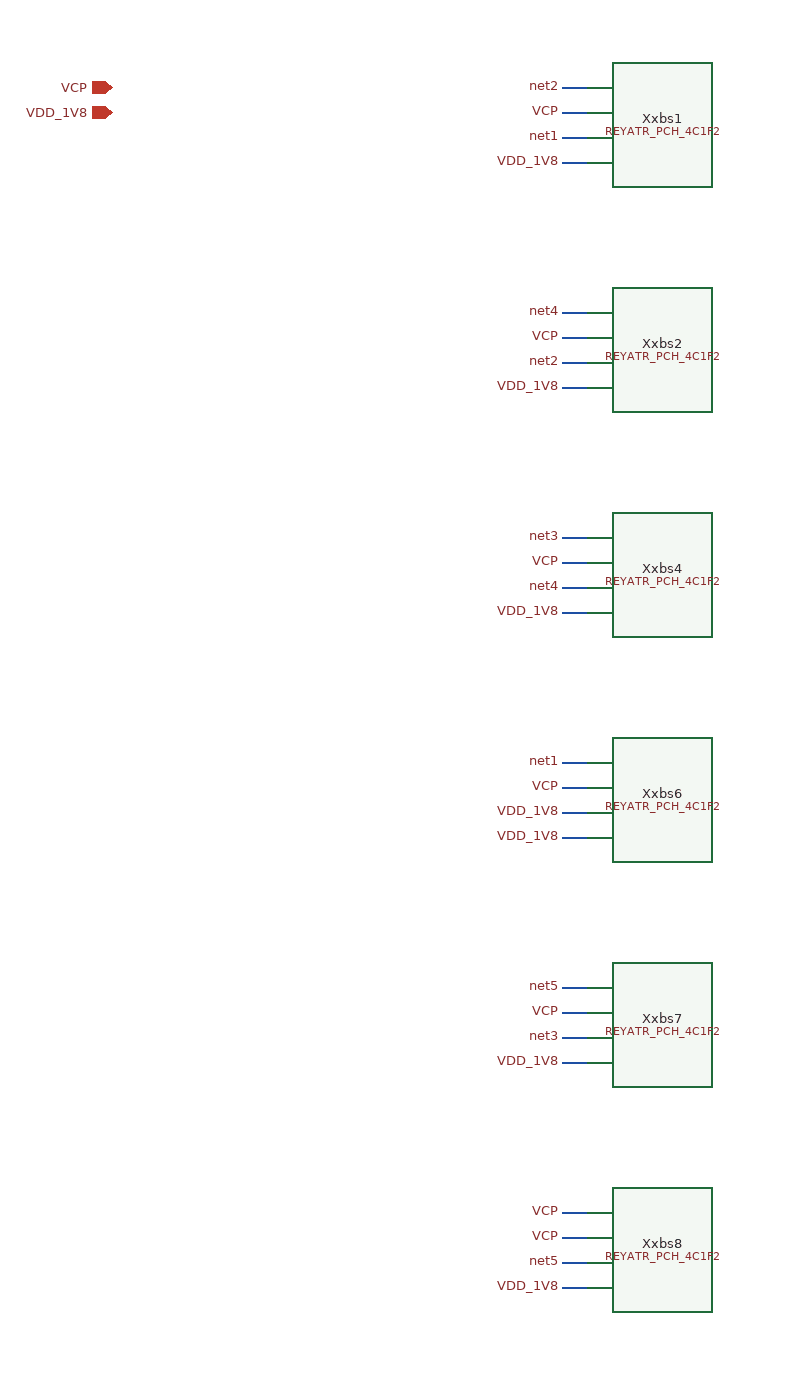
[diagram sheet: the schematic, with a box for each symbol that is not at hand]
v {xschem version=3.0.0 file_version=1.2 }
G {}
K {}
V {}
S {}
E {}
C {devices/iopin.sym} 0 0 0 0 {name=p0 lab=VCP}
C {devices/iopin.sym} 0 20 0 0 {name=p1 lab=VDD_1V8}
C {LELO_TEMP_SKY130A/REYATR_PCH_4C1F2.sym} 400 0 0 0 {name=Xxbs1}
N 360.0 0.0 380.0 0.0 {lab=net2}
C {devices/lab_pin.sym} 360.0 0.0 0 0 {name=l0 sig_type=std_logic lab=net2 }
N 360.0 20.0 380.0 20.0 {lab=VCP}
C {devices/lab_pin.sym} 360.0 20.0 0 0 {name=l1 sig_type=std_logic lab=VCP }
N 360.0 40.0 380.0 40.0 {lab=net1}
C {devices/lab_pin.sym} 360.0 40.0 0 0 {name=l2 sig_type=std_logic lab=net1 }
N 360.0 60.0 380.0 60.0 {lab=VDD_1V8}
C {devices/lab_pin.sym} 360.0 60.0 0 0 {name=l3 sig_type=std_logic lab=VDD_1V8 }
C {LELO_TEMP_SKY130A/REYATR_PCH_4C1F2.sym} 400 180.0 0 0 {name=Xxbs2}
N 360.0 180.0 380.0 180.0 {lab=net4}
C {devices/lab_pin.sym} 360.0 180.0 0 0 {name=l4 sig_type=std_logic lab=net4 }
N 360.0 200.0 380.0 200.0 {lab=VCP}
C {devices/lab_pin.sym} 360.0 200.0 0 0 {name=l5 sig_type=std_logic lab=VCP }
N 360.0 220.0 380.0 220.0 {lab=net2}
C {devices/lab_pin.sym} 360.0 220.0 0 0 {name=l6 sig_type=std_logic lab=net2 }
N 360.0 240.0 380.0 240.0 {lab=VDD_1V8}
C {devices/lab_pin.sym} 360.0 240.0 0 0 {name=l7 sig_type=std_logic lab=VDD_1V8 }
C {LELO_TEMP_SKY130A/REYATR_PCH_4C1F2.sym} 400 360.0 0 0 {name=Xxbs4}
N 360.0 360.0 380.0 360.0 {lab=net3}
C {devices/lab_pin.sym} 360.0 360.0 0 0 {name=l8 sig_type=std_logic lab=net3 }
N 360.0 380.0 380.0 380.0 {lab=VCP}
C {devices/lab_pin.sym} 360.0 380.0 0 0 {name=l9 sig_type=std_logic lab=VCP }
N 360.0 400.0 380.0 400.0 {lab=net4}
C {devices/lab_pin.sym} 360.0 400.0 0 0 {name=l10 sig_type=std_logic lab=net4 }
N 360.0 420.0 380.0 420.0 {lab=VDD_1V8}
C {devices/lab_pin.sym} 360.0 420.0 0 0 {name=l11 sig_type=std_logic lab=VDD_1V8 }
C {LELO_TEMP_SKY130A/REYATR_PCH_4C1F2.sym} 400 540.0 0 0 {name=Xxbs6}
N 360.0 540.0 380.0 540.0 {lab=net1}
C {devices/lab_pin.sym} 360.0 540.0 0 0 {name=l12 sig_type=std_logic lab=net1 }
N 360.0 560.0 380.0 560.0 {lab=VCP}
C {devices/lab_pin.sym} 360.0 560.0 0 0 {name=l13 sig_type=std_logic lab=VCP }
N 360.0 580.0 380.0 580.0 {lab=VDD_1V8}
C {devices/lab_pin.sym} 360.0 580.0 0 0 {name=l14 sig_type=std_logic lab=VDD_1V8 }
N 360.0 600.0 380.0 600.0 {lab=VDD_1V8}
C {devices/lab_pin.sym} 360.0 600.0 0 0 {name=l15 sig_type=std_logic lab=VDD_1V8 }
C {LELO_TEMP_SKY130A/REYATR_PCH_4C1F2.sym} 400 720.0 0 0 {name=Xxbs7}
N 360.0 720.0 380.0 720.0 {lab=net5}
C {devices/lab_pin.sym} 360.0 720.0 0 0 {name=l16 sig_type=std_logic lab=net5 }
N 360.0 740.0 380.0 740.0 {lab=VCP}
C {devices/lab_pin.sym} 360.0 740.0 0 0 {name=l17 sig_type=std_logic lab=VCP }
N 360.0 760.0 380.0 760.0 {lab=net3}
C {devices/lab_pin.sym} 360.0 760.0 0 0 {name=l18 sig_type=std_logic lab=net3 }
N 360.0 780.0 380.0 780.0 {lab=VDD_1V8}
C {devices/lab_pin.sym} 360.0 780.0 0 0 {name=l19 sig_type=std_logic lab=VDD_1V8 }
C {LELO_TEMP_SKY130A/REYATR_PCH_4C1F2.sym} 400 900.0 0 0 {name=Xxbs8}
N 360.0 900.0 380.0 900.0 {lab=VCP}
C {devices/lab_pin.sym} 360.0 900.0 0 0 {name=l20 sig_type=std_logic lab=VCP }
N 360.0 920.0 380.0 920.0 {lab=VCP}
C {devices/lab_pin.sym} 360.0 920.0 0 0 {name=l21 sig_type=std_logic lab=VCP }
N 360.0 940.0 380.0 940.0 {lab=net5}
C {devices/lab_pin.sym} 360.0 940.0 0 0 {name=l22 sig_type=std_logic lab=net5 }
N 360.0 960.0 380.0 960.0 {lab=VDD_1V8}
C {devices/lab_pin.sym} 360.0 960.0 0 0 {name=l23 sig_type=std_logic lab=VDD_1V8 }
